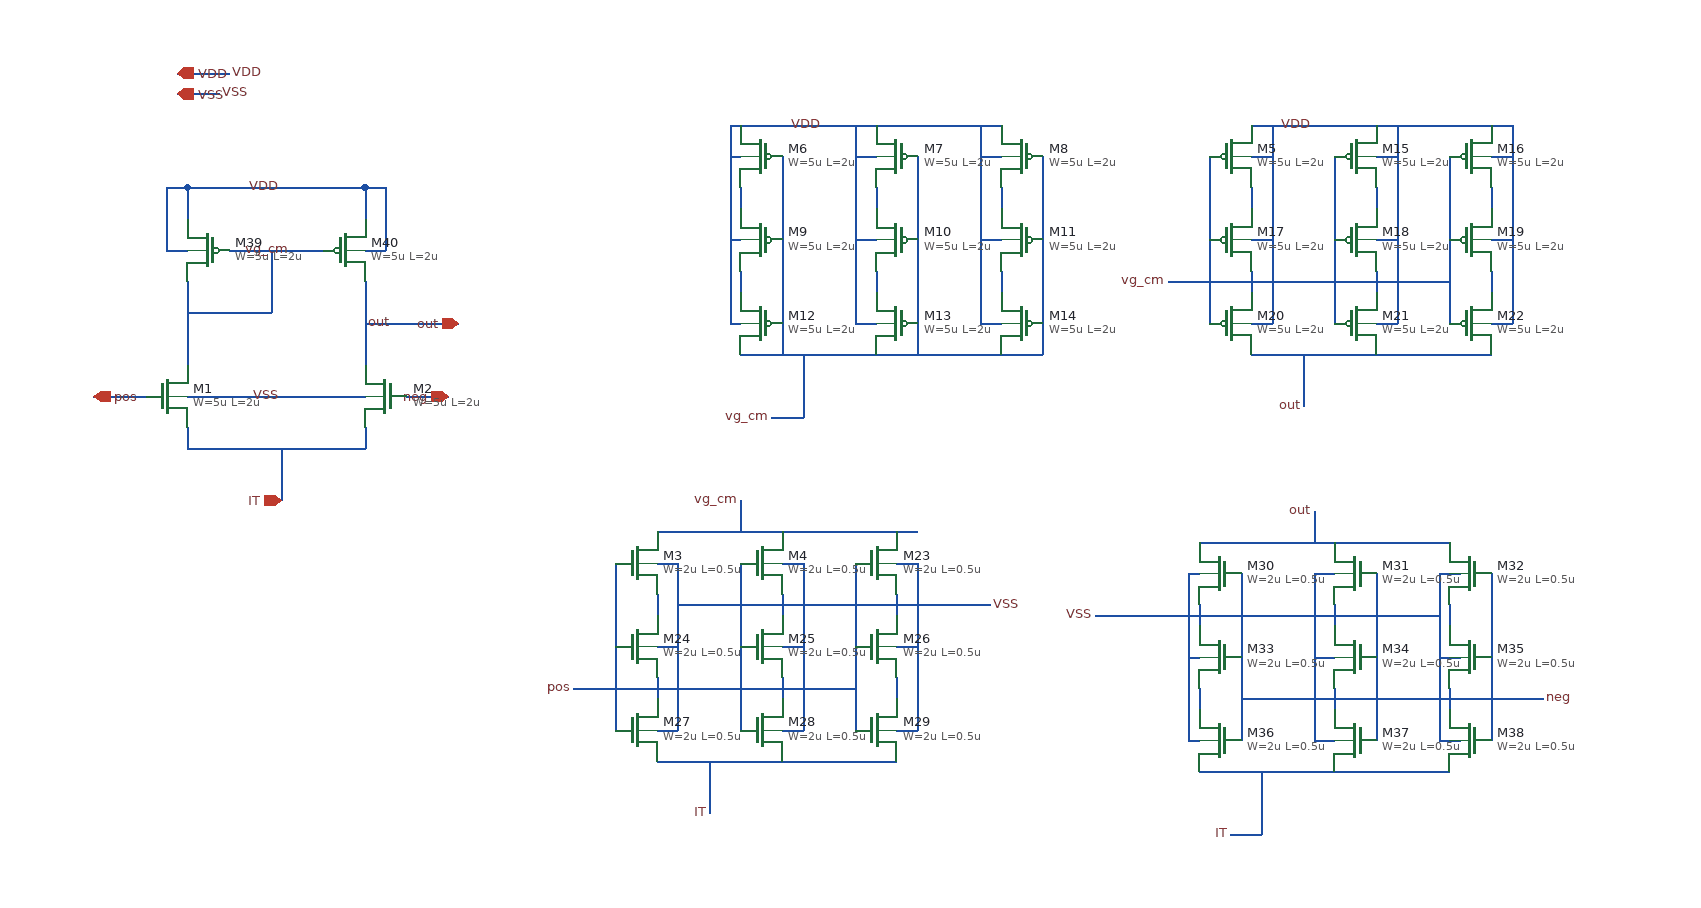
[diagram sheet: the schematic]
v {xschem version=3.4.2 file_version=1.2
}
G {}
K {}
V {}
S {}
E {}
N 100 -90 100 -10 {
lab=vg_cm}
N 270 -90 270 -10 {
lab=out}
N 140 -120 230 -120 {
lab=vg_cm}
N 100 -60 180 -60 {
lab=vg_cm}
N 180 -120 180 -60 {
lab=vg_cm}
N 100 -180 100 -150 {
lab=VDD}
N 100 -180 270 -180 {
lab=VDD}
N 270 -180 270 -150 {
lab=VDD}
N 10 20 60 20 {
lab=pos}
N 310 20 350 20 {
lab=neg}
N 100 50 100 70 {
lab=IT}
N 100 70 270 70 {
lab=IT}
N 270 50 270 70 {
lab=IT}
N 100 20 270 20 {
lab=VSS}
N 270 -120 290 -120 {
lab=VDD}
N 290 -180 290 -120 {
lab=VDD}
N 270 -180 290 -180 {
lab=VDD}
N 80 -120 100 -120 {
lab=VDD}
N 80 -180 80 -120 {
lab=VDD}
N 80 -180 100 -180 {
lab=VDD}
N 190 70 190 120 {
lab=IT}
N 90 -290 140 -290 {
lab=VDD}
N 90 -270 130 -270 {
lab=VSS}
N 270 -50 360 -50 {
lab=out}
N 760 -180 760 -160 {
lab=#net1}
N 630 -180 630 -160 {
lab=#net2}
N 630 -100 630 -80 {
lab=#net3}
N 630 -20 880 -20 {
lab=#net4}
N 670 -210 670 -20 {
lab=#net4}
N 800 -210 800 -20 {
lab=#net4}
N 920 -210 920 -50 {
lab=#net4}
N 630 -240 880 -240 {
lab=#net5}
N 620 -50 630 -50 {
lab=#net5}
N 620 -240 620 -50 {
lab=#net5}
N 620 -240 630 -240 {
lab=#net5}
N 620 -210 630 -210 {
lab=#net5}
N 620 -130 630 -130 {
lab=#net5}
N 740 -50 760 -50 {
lab=#net5}
N 740 -240 740 -50 {
lab=#net5}
N 740 -210 760 -210 {
lab=#net5}
N 760 -100 760 -80 {
lab=#net6}
N 740 -130 760 -130 {
lab=#net5}
N 860 -50 880 -50 {
lab=#net5}
N 860 -240 860 -50 {
lab=#net5}
N 860 -210 880 -210 {
lab=#net5}
N 860 -130 880 -130 {
lab=#net5}
N 880 -180 880 -160 {
lab=#net7}
N 920 -50 920 -20 {
lab=#net4}
N 880 -20 920 -20 {
lab=#net4}
N 880 -100 880 -80 {
lab=#net8}
N 1120 -240 1350 -240 {
lab=#net9}
N 1120 -180 1120 -160 {
lab=#net10}
N 1120 -100 1120 -80 {
lab=#net11}
N 1240 -100 1240 -80 {
lab=#net12}
N 1240 -180 1240 -160 {
lab=#net13}
N 1350 -180 1350 -160 {
lab=#net14}
N 1350 -100 1350 -80 {
lab=#net15}
N 1310 -210 1310 -50 {
lab=#net16}
N 1200 -210 1200 -50 {
lab=#net16}
N 1080 -210 1080 -50 {
lab=#net16}
N 1120 -20 1350 -20 {
lab=#net17}
N 1120 -50 1140 -50 {
lab=#net9}
N 1140 -240 1140 -50 {
lab=#net9}
N 1240 -50 1260 -50 {
lab=#net9}
N 1260 -240 1260 -50 {
lab=#net9}
N 1350 -50 1370 -50 {
lab=#net9}
N 1370 -240 1370 -50 {
lab=#net9}
N 1350 -240 1370 -240 {
lab=#net9}
N 1120 -130 1140 -130 {
lab=#net9}
N 1120 -210 1140 -210 {
lab=#net9}
N 1240 -210 1260 -210 {
lab=#net9}
N 1240 -130 1260 -130 {
lab=#net9}
N 1350 -130 1370 -130 {
lab=#net9}
N 1350 -210 1370 -210 {
lab=#net9}
N 690 -20 690 40 {
lab=#net4}
N 660 40 690 40 {
lab=#net4}
N 1080 -90 1200 -90 {
lab=#net16}
N 1200 -90 1310 -90 {
lab=#net16}
N 1040 -90 1080 -90 {
lab=#net16}
N 1170 -20 1170 30 {
lab=#net17}
N 550 150 780 150 {
lab=#net18}
N 550 210 550 230 {
lab=#net19}
N 550 290 550 310 {
lab=#net20}
N 670 290 670 310 {
lab=#net21}
N 670 210 670 230 {
lab=#net22}
N 780 210 780 230 {
lab=#net23}
N 780 290 780 310 {
lab=#net24}
N 740 180 740 340 {
lab=#net25}
N 630 180 630 340 {
lab=#net25}
N 510 180 510 340 {
lab=#net25}
N 550 370 780 370 {
lab=#net26}
N 550 340 570 340 {
lab=#net27}
N 670 340 690 340 {
lab=#net27}
N 780 340 800 340 {
lab=#net27}
N 780 150 800 150 {
lab=#net18}
N 550 260 570 260 {
lab=#net27}
N 550 180 570 180 {
lab=#net27}
N 670 180 690 180 {
lab=#net27}
N 670 260 690 260 {
lab=#net27}
N 780 260 800 260 {
lab=#net27}
N 780 180 800 180 {
lab=#net27}
N 510 300 630 300 {
lab=#net25}
N 630 300 740 300 {
lab=#net25}
N 470 300 510 300 {
lab=#net25}
N 600 370 600 420 {
lab=#net26}
N 800 180 800 340 {
lab=#net27}
N 690 180 690 340 {
lab=#net27}
N 570 180 570 340 {
lab=#net27}
N 570 220 690 220 {
lab=#net27}
N 690 220 800 220 {
lab=#net27}
N 800 220 870 220 {
lab=#net27}
N 630 120 630 150 {
lab=#net18}
N 1200 220 1200 240 {
lab=#net28}
N 1070 220 1070 240 {
lab=#net29}
N 1070 300 1070 320 {
lab=#net30}
N 1350 190 1350 350 {
lab=#net31}
N 1060 350 1070 350 {
lab=#net32}
N 1060 190 1070 190 {
lab=#net32}
N 1060 270 1070 270 {
lab=#net32}
N 1180 350 1200 350 {
lab=#net32}
N 1180 190 1200 190 {
lab=#net32}
N 1200 300 1200 320 {
lab=#net33}
N 1180 270 1200 270 {
lab=#net32}
N 1300 350 1320 350 {
lab=#net32}
N 1300 190 1320 190 {
lab=#net32}
N 1300 270 1320 270 {
lab=#net32}
N 1310 220 1310 240 {
lab=#net34}
N 1310 300 1310 320 {
lab=#net35}
N 1130 380 1130 440 {
lab=#net36}
N 1100 440 1130 440 {
lab=#net36}
N 1060 190 1060 350 {
lab=#net32}
N 1180 190 1180 350 {
lab=#net32}
N 1300 190 1300 350 {
lab=#net32}
N 1070 380 1310 380 {
lab=#net36}
N 1110 190 1110 350 {
lab=#net31}
N 1240 190 1240 350 {
lab=#net31}
N 1110 310 1240 310 {
lab=#net31}
N 1240 310 1350 310 {
lab=#net31}
N 1180 230 1300 230 {
lab=#net32}
N 1060 230 1180 230 {
lab=#net32}
N 1000 230 1060 230 {
lab=#net32}
N 970 230 1000 230 {
lab=#net32}
N 1350 310 1400 310 {
lab=#net31}
N 1180 130 1180 160 {
lab=#net37}
N 1070 160 1310 160 {
lab=#net37}
C {devices/lab_wire.sym} 190 20 0 0 {name=p9 sig_type=std_logic lab=VSS}
C {devices/lab_wire.sym} 190 -180 0 0 {name=p7 sig_type=std_logic lab=VDD}
C {devices/iopin.sym} 190 120 0 0 {name=p3 lab=IT}
C {devices/iopin.sym} 350 20 0 0 {name=p2 lab=neg}
C {devices/iopin.sym} 10 20 0 1 {name=p1 lab=pos}
C {devices/iopin.sym} 90 -290 0 1 {name=p4 lab=VDD}
C {devices/iopin.sym} 90 -270 0 1 {name=p5 lab=VSS}
C {devices/lab_pin.sym} 140 -290 0 1 {name=p6 sig_type=std_logic lab=VDD}
C {devices/lab_pin.sym} 130 -270 0 1 {name=p8 sig_type=std_logic lab=VSS}
C {devices/iopin.sym} 360 -50 0 0 {name=p10 lab=out}
C {symbols/pfet_03v3.sym} 1100 -210 0 0 {name=M5
L=2u
W=5u
nf=1
m=1
ad="'int((nf+1)/2) * W/nf * 0.18u'"
pd="'2*int((nf+1)/2) * (W/nf + 0.18u)'"
as="'int((nf+2)/2) * W/nf * 0.18u'"
ps="'2*int((nf+2)/2) * (W/nf + 0.18u)'"
nrd="'0.18u / W'" nrs="'0.18u / W'"
sa=0 sb=0 sd=0
model=pfet_03v3
spiceprefix=X
spice_ignore=true}
C {symbols/pfet_03v3.sym} 650 -210 0 1 {name=M6
L=2u
W=5u
nf=1
m=1
ad="'int((nf+1)/2) * W/nf * 0.18u'"
pd="'2*int((nf+1)/2) * (W/nf + 0.18u)'"
as="'int((nf+2)/2) * W/nf * 0.18u'"
ps="'2*int((nf+2)/2) * (W/nf + 0.18u)'"
nrd="'0.18u / W'" nrs="'0.18u / W'"
sa=0 sb=0 sd=0
model=pfet_03v3
spiceprefix=X
spice_ignore=true}
C {symbols/pfet_03v3.sym} 780 -210 0 1 {name=M7
L=2u
W=5u
nf=1
m=1
ad="'int((nf+1)/2) * W/nf * 0.18u'"
pd="'2*int((nf+1)/2) * (W/nf + 0.18u)'"
as="'int((nf+2)/2) * W/nf * 0.18u'"
ps="'2*int((nf+2)/2) * (W/nf + 0.18u)'"
nrd="'0.18u / W'" nrs="'0.18u / W'"
sa=0 sb=0 sd=0
model=pfet_03v3
spiceprefix=X
spice_ignore=true}
C {symbols/pfet_03v3.sym} 900 -210 0 1 {name=M8
L=2u
W=5u
nf=1
m=1
ad="'int((nf+1)/2) * W/nf * 0.18u'"
pd="'2*int((nf+1)/2) * (W/nf + 0.18u)'"
as="'int((nf+2)/2) * W/nf * 0.18u'"
ps="'2*int((nf+2)/2) * (W/nf + 0.18u)'"
nrd="'0.18u / W'" nrs="'0.18u / W'"
sa=0 sb=0 sd=0
model=pfet_03v3
spiceprefix=X
spice_ignore=true}
C {symbols/pfet_03v3.sym} 650 -130 0 1 {name=M9
L=2u
W=5u
nf=1
m=1
ad="'int((nf+1)/2) * W/nf * 0.18u'"
pd="'2*int((nf+1)/2) * (W/nf + 0.18u)'"
as="'int((nf+2)/2) * W/nf * 0.18u'"
ps="'2*int((nf+2)/2) * (W/nf + 0.18u)'"
nrd="'0.18u / W'" nrs="'0.18u / W'"
sa=0 sb=0 sd=0
model=pfet_03v3
spiceprefix=X
spice_ignore=true}
C {symbols/pfet_03v3.sym} 780 -130 0 1 {name=M10
L=2u
W=5u
nf=1
m=1
ad="'int((nf+1)/2) * W/nf * 0.18u'"
pd="'2*int((nf+1)/2) * (W/nf + 0.18u)'"
as="'int((nf+2)/2) * W/nf * 0.18u'"
ps="'2*int((nf+2)/2) * (W/nf + 0.18u)'"
nrd="'0.18u / W'" nrs="'0.18u / W'"
sa=0 sb=0 sd=0
model=pfet_03v3
spiceprefix=X
spice_ignore=true}
C {symbols/pfet_03v3.sym} 900 -130 0 1 {name=M11
L=2u
W=5u
nf=1
m=1
ad="'int((nf+1)/2) * W/nf * 0.18u'"
pd="'2*int((nf+1)/2) * (W/nf + 0.18u)'"
as="'int((nf+2)/2) * W/nf * 0.18u'"
ps="'2*int((nf+2)/2) * (W/nf + 0.18u)'"
nrd="'0.18u / W'" nrs="'0.18u / W'"
sa=0 sb=0 sd=0
model=pfet_03v3
spiceprefix=X
spice_ignore=true}
C {symbols/pfet_03v3.sym} 650 -50 0 1 {name=M12
L=2u
W=5u
nf=1
m=1
ad="'int((nf+1)/2) * W/nf * 0.18u'"
pd="'2*int((nf+1)/2) * (W/nf + 0.18u)'"
as="'int((nf+2)/2) * W/nf * 0.18u'"
ps="'2*int((nf+2)/2) * (W/nf + 0.18u)'"
nrd="'0.18u / W'" nrs="'0.18u / W'"
sa=0 sb=0 sd=0
model=pfet_03v3
spiceprefix=X
spice_ignore=true}
C {symbols/pfet_03v3.sym} 780 -50 0 1 {name=M13
L=2u
W=5u
nf=1
m=1
ad="'int((nf+1)/2) * W/nf * 0.18u'"
pd="'2*int((nf+1)/2) * (W/nf + 0.18u)'"
as="'int((nf+2)/2) * W/nf * 0.18u'"
ps="'2*int((nf+2)/2) * (W/nf + 0.18u)'"
nrd="'0.18u / W'" nrs="'0.18u / W'"
sa=0 sb=0 sd=0
model=pfet_03v3
spiceprefix=X
spice_ignore=true}
C {symbols/pfet_03v3.sym} 900 -50 0 1 {name=M14
L=2u
W=5u
nf=1
m=1
ad="'int((nf+1)/2) * W/nf * 0.18u'"
pd="'2*int((nf+1)/2) * (W/nf + 0.18u)'"
as="'int((nf+2)/2) * W/nf * 0.18u'"
ps="'2*int((nf+2)/2) * (W/nf + 0.18u)'"
nrd="'0.18u / W'" nrs="'0.18u / W'"
sa=0 sb=0 sd=0
model=pfet_03v3
spiceprefix=X
spice_ignore=true}
C {symbols/pfet_03v3.sym} 1220 -210 0 0 {name=M15
L=2u
W=5u
nf=1
m=1
ad="'int((nf+1)/2) * W/nf * 0.18u'"
pd="'2*int((nf+1)/2) * (W/nf + 0.18u)'"
as="'int((nf+2)/2) * W/nf * 0.18u'"
ps="'2*int((nf+2)/2) * (W/nf + 0.18u)'"
nrd="'0.18u / W'" nrs="'0.18u / W'"
sa=0 sb=0 sd=0
model=pfet_03v3
spiceprefix=X
spice_ignore=true}
C {symbols/pfet_03v3.sym} 1330 -210 0 0 {name=M16
L=2u
W=5u
nf=1
m=1
ad="'int((nf+1)/2) * W/nf * 0.18u'"
pd="'2*int((nf+1)/2) * (W/nf + 0.18u)'"
as="'int((nf+2)/2) * W/nf * 0.18u'"
ps="'2*int((nf+2)/2) * (W/nf + 0.18u)'"
nrd="'0.18u / W'" nrs="'0.18u / W'"
sa=0 sb=0 sd=0
model=pfet_03v3
spiceprefix=X
spice_ignore=true}
C {symbols/pfet_03v3.sym} 1100 -130 0 0 {name=M17
L=2u
W=5u
nf=1
m=1
ad="'int((nf+1)/2) * W/nf * 0.18u'"
pd="'2*int((nf+1)/2) * (W/nf + 0.18u)'"
as="'int((nf+2)/2) * W/nf * 0.18u'"
ps="'2*int((nf+2)/2) * (W/nf + 0.18u)'"
nrd="'0.18u / W'" nrs="'0.18u / W'"
sa=0 sb=0 sd=0
model=pfet_03v3
spiceprefix=X
spice_ignore=true}
C {symbols/pfet_03v3.sym} 1220 -130 0 0 {name=M18
L=2u
W=5u
nf=1
m=1
ad="'int((nf+1)/2) * W/nf * 0.18u'"
pd="'2*int((nf+1)/2) * (W/nf + 0.18u)'"
as="'int((nf+2)/2) * W/nf * 0.18u'"
ps="'2*int((nf+2)/2) * (W/nf + 0.18u)'"
nrd="'0.18u / W'" nrs="'0.18u / W'"
sa=0 sb=0 sd=0
model=pfet_03v3
spiceprefix=X
spice_ignore=true}
C {symbols/pfet_03v3.sym} 1330 -130 0 0 {name=M19
L=2u
W=5u
nf=1
m=1
ad="'int((nf+1)/2) * W/nf * 0.18u'"
pd="'2*int((nf+1)/2) * (W/nf + 0.18u)'"
as="'int((nf+2)/2) * W/nf * 0.18u'"
ps="'2*int((nf+2)/2) * (W/nf + 0.18u)'"
nrd="'0.18u / W'" nrs="'0.18u / W'"
sa=0 sb=0 sd=0
model=pfet_03v3
spiceprefix=X
spice_ignore=true}
C {symbols/pfet_03v3.sym} 1100 -50 0 0 {name=M20
L=2u
W=5u
nf=1
m=1
ad="'int((nf+1)/2) * W/nf * 0.18u'"
pd="'2*int((nf+1)/2) * (W/nf + 0.18u)'"
as="'int((nf+2)/2) * W/nf * 0.18u'"
ps="'2*int((nf+2)/2) * (W/nf + 0.18u)'"
nrd="'0.18u / W'" nrs="'0.18u / W'"
sa=0 sb=0 sd=0
model=pfet_03v3
spiceprefix=X
spice_ignore=true}
C {symbols/pfet_03v3.sym} 1220 -50 0 0 {name=M21
L=2u
W=5u
nf=1
m=1
ad="'int((nf+1)/2) * W/nf * 0.18u'"
pd="'2*int((nf+1)/2) * (W/nf + 0.18u)'"
as="'int((nf+2)/2) * W/nf * 0.18u'"
ps="'2*int((nf+2)/2) * (W/nf + 0.18u)'"
nrd="'0.18u / W'" nrs="'0.18u / W'"
sa=0 sb=0 sd=0
model=pfet_03v3
spiceprefix=X
spice_ignore=true}
C {symbols/pfet_03v3.sym} 1330 -50 0 0 {name=M22
L=2u
W=5u
nf=1
m=1
ad="'int((nf+1)/2) * W/nf * 0.18u'"
pd="'2*int((nf+1)/2) * (W/nf + 0.18u)'"
as="'int((nf+2)/2) * W/nf * 0.18u'"
ps="'2*int((nf+2)/2) * (W/nf + 0.18u)'"
nrd="'0.18u / W'" nrs="'0.18u / W'"
sa=0 sb=0 sd=0
model=pfet_03v3
spiceprefix=X
spice_ignore=true}
C {devices/lab_wire.sym} 660 40 0 0 {name=p11 sig_type=std_logic lab=vg_cm
spice_ignore=true}
C {devices/lab_wire.sym} 200 -120 0 0 {name=p12 sig_type=std_logic lab=vg_cm}
C {devices/lab_wire.sym} 710 -240 0 0 {name=p13 sig_type=std_logic lab=VDD
spice_ignore=true}
C {devices/lab_wire.sym} 1180 -240 0 0 {name=p14 sig_type=std_logic lab=VDD
spice_ignore=true}
C {devices/lab_wire.sym} 1040 -90 0 0 {name=p15 sig_type=std_logic lab=vg_cm
spice_ignore=true}
C {devices/lab_wire.sym} 270 -50 0 1 {name=p16 sig_type=std_logic lab=out}
C {devices/lab_wire.sym} 1170 30 0 0 {name=p17 sig_type=std_logic lab=out
spice_ignore=true}
C {symbols/nfet_03v3.sym} 80 20 0 0 {name=M1
L=2u
W=5u
nf=1
m=1
ad="'int((nf+1)/2) * W/nf * 0.18u'"
pd="'2*int((nf+1)/2) * (W/nf + 0.18u)'"
as="'int((nf+2)/2) * W/nf * 0.18u'"
ps="'2*int((nf+2)/2) * (W/nf + 0.18u)'"
nrd="'0.18u / W'" nrs="'0.18u / W'"
sa=0 sb=0 sd=0
model=nfet_03v3
spiceprefix=X
}
C {symbols/nfet_03v3.sym} 290 20 0 1 {name=M2
L=2u
W=5u
nf=1
m=1
ad="'int((nf+1)/2) * W/nf * 0.18u'"
pd="'2*int((nf+1)/2) * (W/nf + 0.18u)'"
as="'int((nf+2)/2) * W/nf * 0.18u'"
ps="'2*int((nf+2)/2) * (W/nf + 0.18u)'"
nrd="'0.18u / W'" nrs="'0.18u / W'"
sa=0 sb=0 sd=0
model=nfet_03v3
spiceprefix=X
}
C {symbols/nfet_03v3.sym} 530 180 0 0 {name=M3
L=0.5u
W=2u
nf=1
m=1
ad="'int((nf+1)/2) * W/nf * 0.18u'"
pd="'2*int((nf+1)/2) * (W/nf + 0.18u)'"
as="'int((nf+2)/2) * W/nf * 0.18u'"
ps="'2*int((nf+2)/2) * (W/nf + 0.18u)'"
nrd="'0.18u / W'" nrs="'0.18u / W'"
sa=0 sb=0 sd=0
model=nfet_03v3
spiceprefix=X
spice_ignore=true}
C {symbols/nfet_03v3.sym} 650 180 0 0 {name=M4
L=0.5u
W=2u
nf=1
m=1
ad="'int((nf+1)/2) * W/nf * 0.18u'"
pd="'2*int((nf+1)/2) * (W/nf + 0.18u)'"
as="'int((nf+2)/2) * W/nf * 0.18u'"
ps="'2*int((nf+2)/2) * (W/nf + 0.18u)'"
nrd="'0.18u / W'" nrs="'0.18u / W'"
sa=0 sb=0 sd=0
model=nfet_03v3
spiceprefix=X
spice_ignore=true}
C {symbols/nfet_03v3.sym} 760 180 0 0 {name=M23
L=0.5u
W=2u
nf=1
m=1
ad="'int((nf+1)/2) * W/nf * 0.18u'"
pd="'2*int((nf+1)/2) * (W/nf + 0.18u)'"
as="'int((nf+2)/2) * W/nf * 0.18u'"
ps="'2*int((nf+2)/2) * (W/nf + 0.18u)'"
nrd="'0.18u / W'" nrs="'0.18u / W'"
sa=0 sb=0 sd=0
model=nfet_03v3
spiceprefix=X
spice_ignore=true}
C {symbols/nfet_03v3.sym} 530 260 0 0 {name=M24
L=0.5u
W=2u
nf=1
m=1
ad="'int((nf+1)/2) * W/nf * 0.18u'"
pd="'2*int((nf+1)/2) * (W/nf + 0.18u)'"
as="'int((nf+2)/2) * W/nf * 0.18u'"
ps="'2*int((nf+2)/2) * (W/nf + 0.18u)'"
nrd="'0.18u / W'" nrs="'0.18u / W'"
sa=0 sb=0 sd=0
model=nfet_03v3
spiceprefix=X
spice_ignore=true}
C {symbols/nfet_03v3.sym} 650 260 0 0 {name=M25
L=0.5u
W=2u
nf=1
m=1
ad="'int((nf+1)/2) * W/nf * 0.18u'"
pd="'2*int((nf+1)/2) * (W/nf + 0.18u)'"
as="'int((nf+2)/2) * W/nf * 0.18u'"
ps="'2*int((nf+2)/2) * (W/nf + 0.18u)'"
nrd="'0.18u / W'" nrs="'0.18u / W'"
sa=0 sb=0 sd=0
model=nfet_03v3
spiceprefix=X
spice_ignore=true}
C {symbols/nfet_03v3.sym} 760 260 0 0 {name=M26
L=0.5u
W=2u
nf=1
m=1
ad="'int((nf+1)/2) * W/nf * 0.18u'"
pd="'2*int((nf+1)/2) * (W/nf + 0.18u)'"
as="'int((nf+2)/2) * W/nf * 0.18u'"
ps="'2*int((nf+2)/2) * (W/nf + 0.18u)'"
nrd="'0.18u / W'" nrs="'0.18u / W'"
sa=0 sb=0 sd=0
model=nfet_03v3
spiceprefix=X
spice_ignore=true}
C {symbols/nfet_03v3.sym} 530 340 0 0 {name=M27
L=0.5u
W=2u
nf=1
m=1
ad="'int((nf+1)/2) * W/nf * 0.18u'"
pd="'2*int((nf+1)/2) * (W/nf + 0.18u)'"
as="'int((nf+2)/2) * W/nf * 0.18u'"
ps="'2*int((nf+2)/2) * (W/nf + 0.18u)'"
nrd="'0.18u / W'" nrs="'0.18u / W'"
sa=0 sb=0 sd=0
model=nfet_03v3
spiceprefix=X
spice_ignore=true}
C {symbols/nfet_03v3.sym} 650 340 0 0 {name=M28
L=0.5u
W=2u
nf=1
m=1
ad="'int((nf+1)/2) * W/nf * 0.18u'"
pd="'2*int((nf+1)/2) * (W/nf + 0.18u)'"
as="'int((nf+2)/2) * W/nf * 0.18u'"
ps="'2*int((nf+2)/2) * (W/nf + 0.18u)'"
nrd="'0.18u / W'" nrs="'0.18u / W'"
sa=0 sb=0 sd=0
model=nfet_03v3
spiceprefix=X
spice_ignore=true}
C {symbols/nfet_03v3.sym} 760 340 0 0 {name=M29
L=0.5u
W=2u
nf=1
m=1
ad="'int((nf+1)/2) * W/nf * 0.18u'"
pd="'2*int((nf+1)/2) * (W/nf + 0.18u)'"
as="'int((nf+2)/2) * W/nf * 0.18u'"
ps="'2*int((nf+2)/2) * (W/nf + 0.18u)'"
nrd="'0.18u / W'" nrs="'0.18u / W'"
sa=0 sb=0 sd=0
model=nfet_03v3
spiceprefix=X
spice_ignore=true}
C {devices/lab_wire.sym} 470 300 0 0 {name=p18 sig_type=std_logic lab=pos
spice_ignore=true}
C {devices/lab_wire.sym} 870 220 0 1 {name=p19 sig_type=std_logic lab=VSS
spice_ignore=true}
C {devices/lab_wire.sym} 600 420 0 0 {name=p20 sig_type=std_logic lab=IT
spice_ignore=true}
C {devices/lab_wire.sym} 630 120 0 0 {name=p21 sig_type=std_logic lab=vg_cm
spice_ignore=true}
C {symbols/nfet_03v3.sym} 1090 190 0 1 {name=M30
L=0.5u
W=2u
nf=1
m=1
ad="'int((nf+1)/2) * W/nf * 0.18u'"
pd="'2*int((nf+1)/2) * (W/nf + 0.18u)'"
as="'int((nf+2)/2) * W/nf * 0.18u'"
ps="'2*int((nf+2)/2) * (W/nf + 0.18u)'"
nrd="'0.18u / W'" nrs="'0.18u / W'"
sa=0 sb=0 sd=0
model=nfet_03v3
spiceprefix=X
spice_ignore=true}
C {symbols/nfet_03v3.sym} 1220 190 0 1 {name=M31
L=0.5u
W=2u
nf=1
m=1
ad="'int((nf+1)/2) * W/nf * 0.18u'"
pd="'2*int((nf+1)/2) * (W/nf + 0.18u)'"
as="'int((nf+2)/2) * W/nf * 0.18u'"
ps="'2*int((nf+2)/2) * (W/nf + 0.18u)'"
nrd="'0.18u / W'" nrs="'0.18u / W'"
sa=0 sb=0 sd=0
model=nfet_03v3
spiceprefix=X
spice_ignore=true}
C {symbols/nfet_03v3.sym} 1330 190 0 1 {name=M32
L=0.5u
W=2u
nf=1
m=1
ad="'int((nf+1)/2) * W/nf * 0.18u'"
pd="'2*int((nf+1)/2) * (W/nf + 0.18u)'"
as="'int((nf+2)/2) * W/nf * 0.18u'"
ps="'2*int((nf+2)/2) * (W/nf + 0.18u)'"
nrd="'0.18u / W'" nrs="'0.18u / W'"
sa=0 sb=0 sd=0
model=nfet_03v3
spiceprefix=X
spice_ignore=true}
C {symbols/nfet_03v3.sym} 1090 270 0 1 {name=M33
L=0.5u
W=2u
nf=1
m=1
ad="'int((nf+1)/2) * W/nf * 0.18u'"
pd="'2*int((nf+1)/2) * (W/nf + 0.18u)'"
as="'int((nf+2)/2) * W/nf * 0.18u'"
ps="'2*int((nf+2)/2) * (W/nf + 0.18u)'"
nrd="'0.18u / W'" nrs="'0.18u / W'"
sa=0 sb=0 sd=0
model=nfet_03v3
spiceprefix=X
spice_ignore=true}
C {symbols/nfet_03v3.sym} 1220 270 0 1 {name=M34
L=0.5u
W=2u
nf=1
m=1
ad="'int((nf+1)/2) * W/nf * 0.18u'"
pd="'2*int((nf+1)/2) * (W/nf + 0.18u)'"
as="'int((nf+2)/2) * W/nf * 0.18u'"
ps="'2*int((nf+2)/2) * (W/nf + 0.18u)'"
nrd="'0.18u / W'" nrs="'0.18u / W'"
sa=0 sb=0 sd=0
model=nfet_03v3
spiceprefix=X
spice_ignore=true}
C {symbols/nfet_03v3.sym} 1330 270 0 1 {name=M35
L=0.5u
W=2u
nf=1
m=1
ad="'int((nf+1)/2) * W/nf * 0.18u'"
pd="'2*int((nf+1)/2) * (W/nf + 0.18u)'"
as="'int((nf+2)/2) * W/nf * 0.18u'"
ps="'2*int((nf+2)/2) * (W/nf + 0.18u)'"
nrd="'0.18u / W'" nrs="'0.18u / W'"
sa=0 sb=0 sd=0
model=nfet_03v3
spiceprefix=X
spice_ignore=true}
C {symbols/nfet_03v3.sym} 1090 350 0 1 {name=M36
L=0.5u
W=2u
nf=1
m=1
ad="'int((nf+1)/2) * W/nf * 0.18u'"
pd="'2*int((nf+1)/2) * (W/nf + 0.18u)'"
as="'int((nf+2)/2) * W/nf * 0.18u'"
ps="'2*int((nf+2)/2) * (W/nf + 0.18u)'"
nrd="'0.18u / W'" nrs="'0.18u / W'"
sa=0 sb=0 sd=0
model=nfet_03v3
spiceprefix=X
spice_ignore=true}
C {symbols/nfet_03v3.sym} 1220 350 0 1 {name=M37
L=0.5u
W=2u
nf=1
m=1
ad="'int((nf+1)/2) * W/nf * 0.18u'"
pd="'2*int((nf+1)/2) * (W/nf + 0.18u)'"
as="'int((nf+2)/2) * W/nf * 0.18u'"
ps="'2*int((nf+2)/2) * (W/nf + 0.18u)'"
nrd="'0.18u / W'" nrs="'0.18u / W'"
sa=0 sb=0 sd=0
model=nfet_03v3
spiceprefix=X
spice_ignore=true}
C {symbols/nfet_03v3.sym} 1330 350 0 1 {name=M38
L=0.5u
W=2u
nf=1
m=1
ad="'int((nf+1)/2) * W/nf * 0.18u'"
pd="'2*int((nf+1)/2) * (W/nf + 0.18u)'"
as="'int((nf+2)/2) * W/nf * 0.18u'"
ps="'2*int((nf+2)/2) * (W/nf + 0.18u)'"
nrd="'0.18u / W'" nrs="'0.18u / W'"
sa=0 sb=0 sd=0
model=nfet_03v3
spiceprefix=X
spice_ignore=true}
C {devices/lab_wire.sym} 970 230 0 0 {name=p23 sig_type=std_logic lab=VSS
spice_ignore=true}
C {devices/lab_wire.sym} 1100 440 0 0 {name=p22 sig_type=std_logic lab=IT
spice_ignore=true}
C {devices/lab_wire.sym} 1400 310 0 1 {name=p24 sig_type=std_logic lab=neg
spice_ignore=true}
C {devices/lab_wire.sym} 1180 130 0 0 {name=p25 sig_type=std_logic lab=out
spice_ignore=true}
C {symbols/pfet_03v3.sym} 120 -120 0 1 {name=M39
L=2u
W=5u
nf=1
m=1
ad="'int((nf+1)/2) * W/nf * 0.18u'"
pd="'2*int((nf+1)/2) * (W/nf + 0.18u)'"
as="'int((nf+2)/2) * W/nf * 0.18u'"
ps="'2*int((nf+2)/2) * (W/nf + 0.18u)'"
nrd="'0.18u / W'" nrs="'0.18u / W'"
sa=0 sb=0 sd=0
model=pfet_03v3
spiceprefix=X
}
C {symbols/pfet_03v3.sym} 250 -120 0 0 {name=M40
L=2u
W=5u
nf=1
m=1
ad="'int((nf+1)/2) * W/nf * 0.18u'"
pd="'2*int((nf+1)/2) * (W/nf + 0.18u)'"
as="'int((nf+2)/2) * W/nf * 0.18u'"
ps="'2*int((nf+2)/2) * (W/nf + 0.18u)'"
nrd="'0.18u / W'" nrs="'0.18u / W'"
sa=0 sb=0 sd=0
model=pfet_03v3
spiceprefix=X
}
